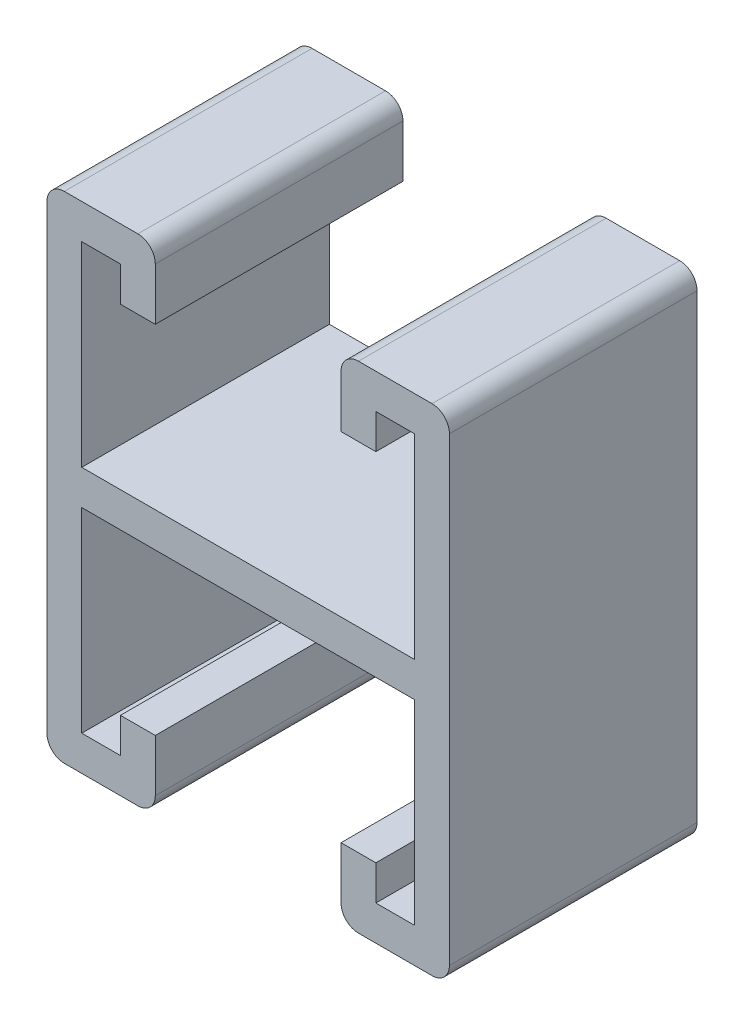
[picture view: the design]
ISO-10303-21;
HEADER;
FILE_DESCRIPTION(('STEP AP214'),'2;1');
FILE_NAME('part.step','',(''),(''),'','','');
FILE_SCHEMA(('AUTOMOTIVE_DESIGN { 1 0 10303 214 1 1 1 1 }'));
ENDSEC;
DATA;
#1=APPLICATION_CONTEXT('core data for automotive mechanical design processes');
#2=APPLICATION_PROTOCOL_DEFINITION('international standard','automotive_design',2000,#1);
#3=PRODUCT_CONTEXT('',#1,'mechanical');
#4=PRODUCT('Part','Part','',(#3));
#5=PRODUCT_RELATED_PRODUCT_CATEGORY('part','',(#4));
#6=PRODUCT_DEFINITION_FORMATION('','',#4);
#7=PRODUCT_DEFINITION_CONTEXT('part definition',#1,'design');
#8=PRODUCT_DEFINITION('design','',#6,#7);
#9=PRODUCT_DEFINITION_SHAPE('','',#8);
#10=(LENGTH_UNIT() NAMED_UNIT(*) SI_UNIT(.MILLI.,.METRE.));
#11=(NAMED_UNIT(*) PLANE_ANGLE_UNIT() SI_UNIT($,.RADIAN.));
#12=(NAMED_UNIT(*) SI_UNIT($,.STERADIAN.) SOLID_ANGLE_UNIT());
#13=UNCERTAINTY_MEASURE_WITH_UNIT(LENGTH_MEASURE(1.E-05),#10,'distance_accuracy_value','');
#14=(GEOMETRIC_REPRESENTATION_CONTEXT(3) GLOBAL_UNCERTAINTY_ASSIGNED_CONTEXT((#13)) GLOBAL_UNIT_ASSIGNED_CONTEXT((#10,
#11,#12)) REPRESENTATION_CONTEXT('',''));
#15=CARTESIAN_POINT('',(0.,0.,0.));
#16=DIRECTION('',(0.,0.,1.));
#17=DIRECTION('',(1.,0.,0.));
#18=AXIS2_PLACEMENT_3D('',#15,#16,#17);
#19=CARTESIAN_POINT('',(9.525,18.25625,12.7));
#20=DIRECTION('',(0.,1.,0.));
#21=DIRECTION('',(0.,0.,1.));
#22=AXIS2_PLACEMENT_3D('',#19,#20,#21);
#23=PLANE('',#22);
#24=DIRECTION('',(1.,0.,0.));
#25=VECTOR('',#24,1.);
#26=CARTESIAN_POINT('',(9.525,18.25625,-12.7));
#27=LINE('',#26,#25);
#28=CARTESIAN_POINT('',(9.525,18.25625,-12.7));
#29=VERTEX_POINT('',#28);
#30=CARTESIAN_POINT('',(13.096875,18.25625,-12.7));
#31=VERTEX_POINT('',#30);
#32=EDGE_CURVE('E303',#29,#31,#27,.T.);
#33=ORIENTED_EDGE('',*,*,#32,.T.);
#34=DIRECTION('',(0.,0.,-1.));
#35=VECTOR('',#34,1.);
#36=CARTESIAN_POINT('',(13.096875,18.25625,12.7));
#37=LINE('',#36,#35);
#38=CARTESIAN_POINT('',(13.096875,18.25625,12.7));
#39=VERTEX_POINT('',#38);
#40=EDGE_CURVE('E11',#39,#31,#37,.T.);
#41=ORIENTED_EDGE('',*,*,#40,.F.);
#42=DIRECTION('',(1.,0.,0.));
#43=VECTOR('',#42,1.);
#44=CARTESIAN_POINT('',(9.525,18.25625,12.7));
#45=LINE('',#44,#43);
#46=CARTESIAN_POINT('',(9.525,18.25625,12.7));
#47=VERTEX_POINT('',#46);
#48=EDGE_CURVE('E373',#47,#39,#45,.T.);
#49=ORIENTED_EDGE('',*,*,#48,.F.);
#50=DIRECTION('',(0.,0.,-1.));
#51=VECTOR('',#50,1.);
#52=CARTESIAN_POINT('',(9.525,18.25625,12.7));
#53=LINE('',#52,#51);
#54=EDGE_CURVE('E299',#47,#29,#53,.T.);
#55=ORIENTED_EDGE('',*,*,#54,.T.);
#56=EDGE_LOOP('',(#33,#41,#49,#55));
#57=FACE_BOUND('',#56,.T.);
#58=ADVANCED_FACE('F39',(#57),#23,.F.);
#59=CARTESIAN_POINT('',(13.096875,21.828125,12.7));
#60=DIRECTION('',(-1.,0.,0.));
#61=DIRECTION('',(0.,-1.,0.));
#62=AXIS2_PLACEMENT_3D('',#59,#60,#61);
#63=PLANE('',#62);
#64=DIRECTION('',(0.,1.,0.));
#65=VECTOR('',#64,1.);
#66=CARTESIAN_POINT('',(13.096875,21.828125,-12.7));
#67=LINE('',#66,#65);
#68=CARTESIAN_POINT('',(13.096875,21.828125,-12.7));
#69=VERTEX_POINT('',#68);
#70=EDGE_CURVE('E306',#31,#69,#67,.T.);
#71=ORIENTED_EDGE('',*,*,#70,.T.);
#72=DIRECTION('',(0.,0.,-1.));
#73=VECTOR('',#72,1.);
#74=CARTESIAN_POINT('',(13.096875,21.828125,12.7));
#75=LINE('',#74,#73);
#76=CARTESIAN_POINT('',(13.096875,21.828125,12.7));
#77=VERTEX_POINT('',#76);
#78=EDGE_CURVE('E50',#77,#69,#75,.T.);
#79=ORIENTED_EDGE('',*,*,#78,.F.);
#80=DIRECTION('',(0.,1.,0.));
#81=VECTOR('',#80,1.);
#82=CARTESIAN_POINT('',(13.096875,21.828125,12.7));
#83=LINE('',#82,#81);
#84=EDGE_CURVE('E185',#39,#77,#83,.T.);
#85=ORIENTED_EDGE('',*,*,#84,.F.);
#86=ORIENTED_EDGE('',*,*,#40,.T.);
#87=EDGE_LOOP('',(#71,#79,#85,#86));
#88=FACE_BOUND('',#87,.T.);
#89=ADVANCED_FACE('F571',(#88),#63,.F.);
#90=CARTESIAN_POINT('',(17.065625,21.828125,12.7));
#91=DIRECTION('',(0.,1.,0.));
#92=DIRECTION('',(0.,0.,1.));
#93=AXIS2_PLACEMENT_3D('',#90,#91,#92);
#94=PLANE('',#93);
#95=DIRECTION('',(1.,0.,0.));
#96=VECTOR('',#95,1.);
#97=CARTESIAN_POINT('',(17.065625,21.828125,-12.7));
#98=LINE('',#97,#96);
#99=CARTESIAN_POINT('',(17.065625,21.828125,-12.7));
#100=VERTEX_POINT('',#99);
#101=EDGE_CURVE('E308',#69,#100,#98,.T.);
#102=ORIENTED_EDGE('',*,*,#101,.T.);
#103=DIRECTION('',(0.,0.,-1.));
#104=VECTOR('',#103,1.);
#105=CARTESIAN_POINT('',(17.065625,21.828125,12.7));
#106=LINE('',#105,#104);
#107=CARTESIAN_POINT('',(17.065625,21.828125,12.7));
#108=VERTEX_POINT('',#107);
#109=EDGE_CURVE('E461',#108,#100,#106,.T.);
#110=ORIENTED_EDGE('',*,*,#109,.F.);
#111=DIRECTION('',(1.,0.,0.));
#112=VECTOR('',#111,1.);
#113=CARTESIAN_POINT('',(17.065625,21.828125,12.7));
#114=LINE('',#113,#112);
#115=EDGE_CURVE('E475',#77,#108,#114,.T.);
#116=ORIENTED_EDGE('',*,*,#115,.F.);
#117=ORIENTED_EDGE('',*,*,#78,.T.);
#118=EDGE_LOOP('',(#102,#110,#116,#117));
#119=FACE_BOUND('',#118,.T.);
#120=ADVANCED_FACE('F468',(#119),#94,.F.);
#121=CARTESIAN_POINT('',(17.065625,1.7859375,12.7));
#122=DIRECTION('',(1.,0.,0.));
#123=DIRECTION('',(0.,1.,0.));
#124=AXIS2_PLACEMENT_3D('',#121,#122,#123);
#125=PLANE('',#124);
#126=DIRECTION('',(0.,-1.,0.));
#127=VECTOR('',#126,1.);
#128=CARTESIAN_POINT('',(17.065625,1.7859375,-12.7));
#129=LINE('',#128,#127);
#130=CARTESIAN_POINT('',(17.065625,1.7859375,-12.7));
#131=VERTEX_POINT('',#130);
#132=EDGE_CURVE('E309',#100,#131,#129,.T.);
#133=ORIENTED_EDGE('',*,*,#132,.T.);
#134=DIRECTION('',(0.,0.,-1.));
#135=VECTOR('',#134,1.);
#136=CARTESIAN_POINT('',(17.065625,1.7859375,12.7));
#137=LINE('',#136,#135);
#138=CARTESIAN_POINT('',(17.065625,1.7859375,12.7));
#139=VERTEX_POINT('',#138);
#140=EDGE_CURVE('E462',#139,#131,#137,.T.);
#141=ORIENTED_EDGE('',*,*,#140,.F.);
#142=DIRECTION('',(0.,-1.,0.));
#143=VECTOR('',#142,1.);
#144=CARTESIAN_POINT('',(17.065625,1.7859375,12.7));
#145=LINE('',#144,#143);
#146=EDGE_CURVE('E489',#108,#139,#145,.T.);
#147=ORIENTED_EDGE('',*,*,#146,.F.);
#148=ORIENTED_EDGE('',*,*,#109,.T.);
#149=EDGE_LOOP('',(#133,#141,#147,#148));
#150=FACE_BOUND('',#149,.T.);
#151=ADVANCED_FACE('F482',(#150),#125,.F.);
#152=CARTESIAN_POINT('',(-17.065625,1.78593749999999,12.7));
#153=DIRECTION('',(0.,-1.,0.));
#154=DIRECTION('',(1.,0.,0.));
#155=AXIS2_PLACEMENT_3D('',#152,#153,#154);
#156=PLANE('',#155);
#157=DIRECTION('',(-1.,0.,0.));
#158=VECTOR('',#157,1.);
#159=CARTESIAN_POINT('',(-17.065625,1.78593749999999,-12.7));
#160=LINE('',#159,#158);
#161=CARTESIAN_POINT('',(-17.065625,1.78593749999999,-12.7));
#162=VERTEX_POINT('',#161);
#163=EDGE_CURVE('E315',#131,#162,#160,.T.);
#164=ORIENTED_EDGE('',*,*,#163,.T.);
#165=DIRECTION('',(0.,0.,-1.));
#166=VECTOR('',#165,1.);
#167=CARTESIAN_POINT('',(-17.065625,1.78593749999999,12.7));
#168=LINE('',#167,#166);
#169=CARTESIAN_POINT('',(-17.065625,1.78593749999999,12.7));
#170=VERTEX_POINT('',#169);
#171=EDGE_CURVE('E457',#170,#162,#168,.T.);
#172=ORIENTED_EDGE('',*,*,#171,.F.);
#173=DIRECTION('',(-1.,0.,0.));
#174=VECTOR('',#173,1.);
#175=CARTESIAN_POINT('',(-17.065625,1.78593749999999,12.7));
#176=LINE('',#175,#174);
#177=EDGE_CURVE('E487',#139,#170,#176,.T.);
#178=ORIENTED_EDGE('',*,*,#177,.F.);
#179=ORIENTED_EDGE('',*,*,#140,.T.);
#180=EDGE_LOOP('',(#164,#172,#178,#179));
#181=FACE_BOUND('',#180,.T.);
#182=ADVANCED_FACE('F483',(#181),#156,.F.);
#183=CARTESIAN_POINT('',(-17.065625,21.828125,12.7));
#184=DIRECTION('',(-1.,0.,0.));
#185=DIRECTION('',(0.,-1.,0.));
#186=AXIS2_PLACEMENT_3D('',#183,#184,#185);
#187=PLANE('',#186);
#188=DIRECTION('',(0.,1.,0.));
#189=VECTOR('',#188,1.);
#190=CARTESIAN_POINT('',(-17.065625,21.828125,-12.7));
#191=LINE('',#190,#189);
#192=CARTESIAN_POINT('',(-17.065625,21.828125,-12.7));
#193=VERTEX_POINT('',#192);
#194=EDGE_CURVE('E313',#162,#193,#191,.T.);
#195=ORIENTED_EDGE('',*,*,#194,.T.);
#196=DIRECTION('',(0.,0.,-1.));
#197=VECTOR('',#196,1.);
#198=CARTESIAN_POINT('',(-17.065625,21.828125,12.7));
#199=LINE('',#198,#197);
#200=CARTESIAN_POINT('',(-17.065625,21.828125,12.7));
#201=VERTEX_POINT('',#200);
#202=EDGE_CURVE('E453',#201,#193,#199,.T.);
#203=ORIENTED_EDGE('',*,*,#202,.F.);
#204=DIRECTION('',(0.,1.,0.));
#205=VECTOR('',#204,1.);
#206=CARTESIAN_POINT('',(-17.065625,21.828125,12.7));
#207=LINE('',#206,#205);
#208=EDGE_CURVE('E490',#170,#201,#207,.T.);
#209=ORIENTED_EDGE('',*,*,#208,.F.);
#210=ORIENTED_EDGE('',*,*,#171,.T.);
#211=EDGE_LOOP('',(#195,#203,#209,#210));
#212=FACE_BOUND('',#211,.T.);
#213=ADVANCED_FACE('F581',(#212),#187,.F.);
#214=CARTESIAN_POINT('',(-13.096875,21.828125,12.7));
#215=DIRECTION('',(0.,1.,0.));
#216=DIRECTION('',(0.,0.,1.));
#217=AXIS2_PLACEMENT_3D('',#214,#215,#216);
#218=PLANE('',#217);
#219=DIRECTION('',(1.,0.,0.));
#220=VECTOR('',#219,1.);
#221=CARTESIAN_POINT('',(-13.096875,21.828125,-12.7));
#222=LINE('',#221,#220);
#223=CARTESIAN_POINT('',(-13.096875,21.828125,-12.7));
#224=VERTEX_POINT('',#223);
#225=EDGE_CURVE('E317',#193,#224,#222,.T.);
#226=ORIENTED_EDGE('',*,*,#225,.T.);
#227=DIRECTION('',(0.,0.,-1.));
#228=VECTOR('',#227,1.);
#229=CARTESIAN_POINT('',(-13.096875,21.828125,12.7));
#230=LINE('',#229,#228);
#231=CARTESIAN_POINT('',(-13.096875,21.828125,12.7));
#232=VERTEX_POINT('',#231);
#233=EDGE_CURVE('E455',#232,#224,#230,.T.);
#234=ORIENTED_EDGE('',*,*,#233,.F.);
#235=DIRECTION('',(1.,0.,0.));
#236=VECTOR('',#235,1.);
#237=CARTESIAN_POINT('',(-13.096875,21.828125,12.7));
#238=LINE('',#237,#236);
#239=EDGE_CURVE('E495',#201,#232,#238,.T.);
#240=ORIENTED_EDGE('',*,*,#239,.F.);
#241=ORIENTED_EDGE('',*,*,#202,.T.);
#242=EDGE_LOOP('',(#226,#234,#240,#241));
#243=FACE_BOUND('',#242,.T.);
#244=ADVANCED_FACE('F589',(#243),#218,.F.);
#245=CARTESIAN_POINT('',(-13.096875,21.828125,12.7));
#246=DIRECTION('',(1.,0.,0.));
#247=DIRECTION('',(0.,0.,-1.));
#248=AXIS2_PLACEMENT_3D('',#245,#246,#247);
#249=PLANE('',#248);
#250=DIRECTION('',(0.,-1.,0.));
#251=VECTOR('',#250,1.);
#252=CARTESIAN_POINT('',(-13.096875,21.828125,-12.7));
#253=LINE('',#252,#251);
#254=CARTESIAN_POINT('',(-13.096875,18.25625,-12.7));
#255=VERTEX_POINT('',#254);
#256=EDGE_CURVE('E319',#224,#255,#253,.T.);
#257=ORIENTED_EDGE('',*,*,#256,.T.);
#258=DIRECTION('',(0.,0.,-1.));
#259=VECTOR('',#258,1.);
#260=CARTESIAN_POINT('',(-13.096875,18.25625,12.7));
#261=LINE('',#260,#259);
#262=CARTESIAN_POINT('',(-13.096875,18.25625,12.7));
#263=VERTEX_POINT('',#262);
#264=EDGE_CURVE('E446',#263,#255,#261,.T.);
#265=ORIENTED_EDGE('',*,*,#264,.F.);
#266=DIRECTION('',(0.,-1.,0.));
#267=VECTOR('',#266,1.);
#268=CARTESIAN_POINT('',(-13.096875,21.828125,12.7));
#269=LINE('',#268,#267);
#270=EDGE_CURVE('E498',#232,#263,#269,.T.);
#271=ORIENTED_EDGE('',*,*,#270,.F.);
#272=ORIENTED_EDGE('',*,*,#233,.T.);
#273=EDGE_LOOP('',(#257,#265,#271,#272));
#274=FACE_BOUND('',#273,.T.);
#275=ADVANCED_FACE('F592',(#274),#249,.F.);
#276=CARTESIAN_POINT('',(-13.096875,18.25625,12.7));
#277=DIRECTION('',(0.,1.,0.));
#278=DIRECTION('',(0.,0.,1.));
#279=AXIS2_PLACEMENT_3D('',#276,#277,#278);
#280=PLANE('',#279);
#281=DIRECTION('',(1.,0.,0.));
#282=VECTOR('',#281,1.);
#283=CARTESIAN_POINT('',(-13.096875,18.25625,-12.7));
#284=LINE('',#283,#282);
#285=CARTESIAN_POINT('',(-9.525,18.25625,-12.7));
#286=VERTEX_POINT('',#285);
#287=EDGE_CURVE('E318',#255,#286,#284,.T.);
#288=ORIENTED_EDGE('',*,*,#287,.T.);
#289=DIRECTION('',(0.,0.,-1.));
#290=VECTOR('',#289,1.);
#291=CARTESIAN_POINT('',(-9.525,18.25625,12.7));
#292=LINE('',#291,#290);
#293=CARTESIAN_POINT('',(-9.525,18.25625,12.7));
#294=VERTEX_POINT('',#293);
#295=EDGE_CURVE('E447',#294,#286,#292,.T.);
#296=ORIENTED_EDGE('',*,*,#295,.F.);
#297=DIRECTION('',(1.,0.,0.));
#298=VECTOR('',#297,1.);
#299=CARTESIAN_POINT('',(-13.096875,18.25625,12.7));
#300=LINE('',#299,#298);
#301=EDGE_CURVE('E499',#263,#294,#300,.T.);
#302=ORIENTED_EDGE('',*,*,#301,.F.);
#303=ORIENTED_EDGE('',*,*,#264,.T.);
#304=EDGE_LOOP('',(#288,#296,#302,#303));
#305=FACE_BOUND('',#304,.T.);
#306=ADVANCED_FACE('F593',(#305),#280,.F.);
#307=CARTESIAN_POINT('',(-9.525,23.6140625,12.7));
#308=DIRECTION('',(-1.,0.,0.));
#309=DIRECTION('',(0.,0.,1.));
#310=AXIS2_PLACEMENT_3D('',#307,#308,#309);
#311=PLANE('',#310);
#312=DIRECTION('',(0.,1.,0.));
#313=VECTOR('',#312,1.);
#314=CARTESIAN_POINT('',(-9.525,23.6140625,-12.7));
#315=LINE('',#314,#313);
#316=CARTESIAN_POINT('',(-9.525,23.6140625,-12.7));
#317=VERTEX_POINT('',#316);
#318=EDGE_CURVE('E325',#286,#317,#315,.T.);
#319=ORIENTED_EDGE('',*,*,#318,.T.);
#320=DIRECTION('',(0.,0.,-1.));
#321=VECTOR('',#320,1.);
#322=CARTESIAN_POINT('',(-9.525,23.6140625,12.7));
#323=LINE('',#322,#321);
#324=CARTESIAN_POINT('',(-9.525,23.6140625,12.7));
#325=VERTEX_POINT('',#324);
#326=EDGE_CURVE('E442',#325,#317,#323,.T.);
#327=ORIENTED_EDGE('',*,*,#326,.F.);
#328=DIRECTION('',(0.,1.,0.));
#329=VECTOR('',#328,1.);
#330=CARTESIAN_POINT('',(-9.525,23.6140625,12.7));
#331=LINE('',#330,#329);
#332=EDGE_CURVE('E505',#294,#325,#331,.T.);
#333=ORIENTED_EDGE('',*,*,#332,.F.);
#334=ORIENTED_EDGE('',*,*,#295,.T.);
#335=EDGE_LOOP('',(#319,#327,#333,#334));
#336=FACE_BOUND('',#335,.T.);
#337=ADVANCED_FACE('F599',(#336),#311,.F.);
#338=CARTESIAN_POINT('',(-11.3109375,23.6140625,12.7));
#339=DIRECTION('',(0.,0.,-1.));
#340=DIRECTION('',(-1.,0.,0.));
#341=AXIS2_PLACEMENT_3D('',#338,#339,#340);
#342=CYLINDRICAL_SURFACE('',#341,1.7859375);
#343=CARTESIAN_POINT('',(-11.3109375,23.6140625,-12.7));
#344=DIRECTION('',(0.,0.,1.));
#345=DIRECTION('',(-1.,0.,0.));
#346=AXIS2_PLACEMENT_3D('',#343,#344,#345);
#347=CIRCLE('',#346,1.7859375);
#348=CARTESIAN_POINT('',(-11.3109375,25.4,-12.7));
#349=VERTEX_POINT('',#348);
#350=EDGE_CURVE('E321',#317,#349,#347,.T.);
#351=ORIENTED_EDGE('',*,*,#350,.T.);
#352=DIRECTION('',(0.,0.,-1.));
#353=VECTOR('',#352,1.);
#354=CARTESIAN_POINT('',(-11.3109375,25.4,12.7));
#355=LINE('',#354,#353);
#356=CARTESIAN_POINT('',(-11.3109375,25.4,12.7));
#357=VERTEX_POINT('',#356);
#358=EDGE_CURVE('E439',#357,#349,#355,.T.);
#359=ORIENTED_EDGE('',*,*,#358,.F.);
#360=CARTESIAN_POINT('',(-11.3109375,23.6140625,12.7));
#361=DIRECTION('',(0.,0.,1.));
#362=DIRECTION('',(-1.,0.,0.));
#363=AXIS2_PLACEMENT_3D('',#360,#361,#362);
#364=CIRCLE('',#363,1.7859375);
#365=EDGE_CURVE('E502',#325,#357,#364,.T.);
#366=ORIENTED_EDGE('',*,*,#365,.F.);
#367=ORIENTED_EDGE('',*,*,#326,.T.);
#368=EDGE_LOOP('',(#351,#359,#366,#367));
#369=FACE_BOUND('',#368,.T.);
#370=ADVANCED_FACE('F604',(#369),#342,.T.);
#371=CARTESIAN_POINT('',(-11.3109375,25.4,12.7));
#372=DIRECTION('',(0.,-1.,0.));
#373=DIRECTION('',(1.,0.,0.));
#374=AXIS2_PLACEMENT_3D('',#371,#372,#373);
#375=PLANE('',#374);
#376=DIRECTION('',(-1.,0.,0.));
#377=VECTOR('',#376,1.);
#378=CARTESIAN_POINT('',(-11.3109375,25.4,-12.7));
#379=LINE('',#378,#377);
#380=CARTESIAN_POINT('',(-18.8515625,25.4,-12.7));
#381=VERTEX_POINT('',#380);
#382=EDGE_CURVE('E328',#349,#381,#379,.T.);
#383=ORIENTED_EDGE('',*,*,#382,.T.);
#384=DIRECTION('',(0.,0.,-1.));
#385=VECTOR('',#384,1.);
#386=CARTESIAN_POINT('',(-18.8515625,25.4,12.7));
#387=LINE('',#386,#385);
#388=CARTESIAN_POINT('',(-18.8515625,25.4,12.7));
#389=VERTEX_POINT('',#388);
#390=EDGE_CURVE('E440',#389,#381,#387,.T.);
#391=ORIENTED_EDGE('',*,*,#390,.F.);
#392=DIRECTION('',(-1.,0.,0.));
#393=VECTOR('',#392,1.);
#394=CARTESIAN_POINT('',(-11.3109375,25.4,12.7));
#395=LINE('',#394,#393);
#396=EDGE_CURVE('E506',#357,#389,#395,.T.);
#397=ORIENTED_EDGE('',*,*,#396,.F.);
#398=ORIENTED_EDGE('',*,*,#358,.T.);
#399=EDGE_LOOP('',(#383,#391,#397,#398));
#400=FACE_BOUND('',#399,.T.);
#401=ADVANCED_FACE('F609',(#400),#375,.F.);
#402=CARTESIAN_POINT('',(-18.8515625,23.6140625,12.7));
#403=DIRECTION('',(0.,0.,-1.));
#404=DIRECTION('',(-1.,0.,0.));
#405=AXIS2_PLACEMENT_3D('',#402,#403,#404);
#406=CYLINDRICAL_SURFACE('',#405,1.7859375);
#407=CARTESIAN_POINT('',(-18.8515625,23.6140625,-12.7));
#408=DIRECTION('',(0.,0.,1.));
#409=DIRECTION('',(-1.,0.,0.));
#410=AXIS2_PLACEMENT_3D('',#407,#408,#409);
#411=CIRCLE('',#410,1.7859375);
#412=CARTESIAN_POINT('',(-20.6375,23.6140625,-12.7));
#413=VERTEX_POINT('',#412);
#414=EDGE_CURVE('E327',#381,#413,#411,.T.);
#415=ORIENTED_EDGE('',*,*,#414,.T.);
#416=DIRECTION('',(0.,0.,-1.));
#417=VECTOR('',#416,1.);
#418=CARTESIAN_POINT('',(-20.6375,23.6140625,12.7));
#419=LINE('',#418,#417);
#420=CARTESIAN_POINT('',(-20.6375,23.6140625,12.7));
#421=VERTEX_POINT('',#420);
#422=EDGE_CURVE('E432',#421,#413,#419,.T.);
#423=ORIENTED_EDGE('',*,*,#422,.F.);
#424=CARTESIAN_POINT('',(-18.8515625,23.6140625,12.7));
#425=DIRECTION('',(0.,0.,1.));
#426=DIRECTION('',(-1.,0.,0.));
#427=AXIS2_PLACEMENT_3D('',#424,#425,#426);
#428=CIRCLE('',#427,1.7859375);
#429=EDGE_CURVE('E507',#389,#421,#428,.T.);
#430=ORIENTED_EDGE('',*,*,#429,.F.);
#431=ORIENTED_EDGE('',*,*,#390,.T.);
#432=EDGE_LOOP('',(#415,#423,#430,#431));
#433=FACE_BOUND('',#432,.T.);
#434=ADVANCED_FACE('F612',(#433),#406,.T.);
#435=CARTESIAN_POINT('',(-20.6375,23.6140625,12.7));
#436=DIRECTION('',(1.,0.,0.));
#437=DIRECTION('',(0.,1.,0.));
#438=AXIS2_PLACEMENT_3D('',#435,#436,#437);
#439=PLANE('',#438);
#440=DIRECTION('',(0.,-1.,0.));
#441=VECTOR('',#440,1.);
#442=CARTESIAN_POINT('',(-20.6375,23.6140625,-12.7));
#443=LINE('',#442,#441);
#444=CARTESIAN_POINT('',(-20.6375,-23.6140625,-12.7));
#445=VERTEX_POINT('',#444);
#446=EDGE_CURVE('E326',#413,#445,#443,.T.);
#447=ORIENTED_EDGE('',*,*,#446,.T.);
#448=DIRECTION('',(0.,0.,-1.));
#449=VECTOR('',#448,1.);
#450=CARTESIAN_POINT('',(-20.6375,-23.6140625,12.7));
#451=LINE('',#450,#449);
#452=CARTESIAN_POINT('',(-20.6375,-23.6140625,12.7));
#453=VERTEX_POINT('',#452);
#454=EDGE_CURVE('E431',#453,#445,#451,.T.);
#455=ORIENTED_EDGE('',*,*,#454,.F.);
#456=DIRECTION('',(0.,-1.,0.));
#457=VECTOR('',#456,1.);
#458=CARTESIAN_POINT('',(-20.6375,23.6140625,12.7));
#459=LINE('',#458,#457);
#460=EDGE_CURVE('E509',#421,#453,#459,.T.);
#461=ORIENTED_EDGE('',*,*,#460,.F.);
#462=ORIENTED_EDGE('',*,*,#422,.T.);
#463=EDGE_LOOP('',(#447,#455,#461,#462));
#464=FACE_BOUND('',#463,.T.);
#465=ADVANCED_FACE('F613',(#464),#439,.F.);
#466=CARTESIAN_POINT('',(-18.8515625,-23.6140625,12.7));
#467=DIRECTION('',(0.,0.,-1.));
#468=DIRECTION('',(-1.,0.,0.));
#469=AXIS2_PLACEMENT_3D('',#466,#467,#468);
#470=CYLINDRICAL_SURFACE('',#469,1.7859375);
#471=CARTESIAN_POINT('',(-18.8515625,-23.6140625,-12.7));
#472=DIRECTION('',(0.,0.,1.));
#473=DIRECTION('',(1.,0.,0.));
#474=AXIS2_PLACEMENT_3D('',#471,#472,#473);
#475=CIRCLE('',#474,1.7859375);
#476=CARTESIAN_POINT('',(-18.8515625,-25.4,-12.7));
#477=VERTEX_POINT('',#476);
#478=EDGE_CURVE('E334',#445,#477,#475,.T.);
#479=ORIENTED_EDGE('',*,*,#478,.T.);
#480=DIRECTION('',(0.,0.,-1.));
#481=VECTOR('',#480,1.);
#482=CARTESIAN_POINT('',(-18.8515625,-25.4,12.7));
#483=LINE('',#482,#481);
#484=CARTESIAN_POINT('',(-18.8515625,-25.4,12.7));
#485=VERTEX_POINT('',#484);
#486=EDGE_CURVE('E426',#485,#477,#483,.T.);
#487=ORIENTED_EDGE('',*,*,#486,.F.);
#488=CARTESIAN_POINT('',(-18.8515625,-23.6140625,12.7));
#489=DIRECTION('',(0.,0.,1.));
#490=DIRECTION('',(1.,0.,0.));
#491=AXIS2_PLACEMENT_3D('',#488,#489,#490);
#492=CIRCLE('',#491,1.7859375);
#493=EDGE_CURVE('E515',#453,#485,#492,.T.);
#494=ORIENTED_EDGE('',*,*,#493,.F.);
#495=ORIENTED_EDGE('',*,*,#454,.T.);
#496=EDGE_LOOP('',(#479,#487,#494,#495));
#497=FACE_BOUND('',#496,.T.);
#498=ADVANCED_FACE('F620',(#497),#470,.T.);
#499=CARTESIAN_POINT('',(-11.3109375,-25.4,12.7));
#500=DIRECTION('',(0.,1.,0.));
#501=DIRECTION('',(-1.,0.,0.));
#502=AXIS2_PLACEMENT_3D('',#499,#500,#501);
#503=PLANE('',#502);
#504=DIRECTION('',(1.,0.,0.));
#505=VECTOR('',#504,1.);
#506=CARTESIAN_POINT('',(-11.3109375,-25.4,-12.7));
#507=LINE('',#506,#505);
#508=CARTESIAN_POINT('',(-11.3109375,-25.4,-12.7));
#509=VERTEX_POINT('',#508);
#510=EDGE_CURVE('E331',#477,#509,#507,.T.);
#511=ORIENTED_EDGE('',*,*,#510,.T.);
#512=DIRECTION('',(0.,0.,-1.));
#513=VECTOR('',#512,1.);
#514=CARTESIAN_POINT('',(-11.3109375,-25.4,12.7));
#515=LINE('',#514,#513);
#516=CARTESIAN_POINT('',(-11.3109375,-25.4,12.7));
#517=VERTEX_POINT('',#516);
#518=EDGE_CURVE('E424',#517,#509,#515,.T.);
#519=ORIENTED_EDGE('',*,*,#518,.F.);
#520=DIRECTION('',(1.,0.,0.));
#521=VECTOR('',#520,1.);
#522=CARTESIAN_POINT('',(-11.3109375,-25.4,12.7));
#523=LINE('',#522,#521);
#524=EDGE_CURVE('E511',#485,#517,#523,.T.);
#525=ORIENTED_EDGE('',*,*,#524,.F.);
#526=ORIENTED_EDGE('',*,*,#486,.T.);
#527=EDGE_LOOP('',(#511,#519,#525,#526));
#528=FACE_BOUND('',#527,.T.);
#529=ADVANCED_FACE('F621',(#528),#503,.F.);
#530=CARTESIAN_POINT('',(-11.3109375,-23.6140625,12.7));
#531=DIRECTION('',(0.,0.,-1.));
#532=DIRECTION('',(-1.,0.,0.));
#533=AXIS2_PLACEMENT_3D('',#530,#531,#532);
#534=CYLINDRICAL_SURFACE('',#533,1.7859375);
#535=CARTESIAN_POINT('',(-11.3109375,-23.6140625,-12.7));
#536=DIRECTION('',(0.,0.,1.));
#537=DIRECTION('',(1.,0.,0.));
#538=AXIS2_PLACEMENT_3D('',#535,#536,#537);
#539=CIRCLE('',#538,1.7859375);
#540=CARTESIAN_POINT('',(-9.525,-23.6140625,-12.7));
#541=VERTEX_POINT('',#540);
#542=EDGE_CURVE('E337',#509,#541,#539,.T.);
#543=ORIENTED_EDGE('',*,*,#542,.T.);
#544=DIRECTION('',(0.,0.,-1.));
#545=VECTOR('',#544,1.);
#546=CARTESIAN_POINT('',(-9.525,-23.6140625,12.7));
#547=LINE('',#546,#545);
#548=CARTESIAN_POINT('',(-9.525,-23.6140625,12.7));
#549=VERTEX_POINT('',#548);
#550=EDGE_CURVE('E422',#549,#541,#547,.T.);
#551=ORIENTED_EDGE('',*,*,#550,.F.);
#552=CARTESIAN_POINT('',(-11.3109375,-23.6140625,12.7));
#553=DIRECTION('',(0.,0.,1.));
#554=DIRECTION('',(1.,0.,0.));
#555=AXIS2_PLACEMENT_3D('',#552,#553,#554);
#556=CIRCLE('',#555,1.7859375);
#557=EDGE_CURVE('E517',#517,#549,#556,.T.);
#558=ORIENTED_EDGE('',*,*,#557,.F.);
#559=ORIENTED_EDGE('',*,*,#518,.T.);
#560=EDGE_LOOP('',(#543,#551,#558,#559));
#561=FACE_BOUND('',#560,.T.);
#562=ADVANCED_FACE('F630',(#561),#534,.T.);
#563=CARTESIAN_POINT('',(-9.525,-23.6140625,12.7));
#564=DIRECTION('',(-1.,0.,0.));
#565=DIRECTION('',(0.,0.,1.));
#566=AXIS2_PLACEMENT_3D('',#563,#564,#565);
#567=PLANE('',#566);
#568=DIRECTION('',(0.,1.,0.));
#569=VECTOR('',#568,1.);
#570=CARTESIAN_POINT('',(-9.525,-23.6140625,-12.7));
#571=LINE('',#570,#569);
#572=CARTESIAN_POINT('',(-9.525,-18.25625,-12.7));
#573=VERTEX_POINT('',#572);
#574=EDGE_CURVE('E336',#541,#573,#571,.T.);
#575=ORIENTED_EDGE('',*,*,#574,.T.);
#576=DIRECTION('',(0.,0.,-1.));
#577=VECTOR('',#576,1.);
#578=CARTESIAN_POINT('',(-9.525,-18.25625,12.7));
#579=LINE('',#578,#577);
#580=CARTESIAN_POINT('',(-9.525,-18.25625,12.7));
#581=VERTEX_POINT('',#580);
#582=EDGE_CURVE('E416',#581,#573,#579,.T.);
#583=ORIENTED_EDGE('',*,*,#582,.F.);
#584=DIRECTION('',(0.,1.,0.));
#585=VECTOR('',#584,1.);
#586=CARTESIAN_POINT('',(-9.525,-23.6140625,12.7));
#587=LINE('',#586,#585);
#588=EDGE_CURVE('E519',#549,#581,#587,.T.);
#589=ORIENTED_EDGE('',*,*,#588,.F.);
#590=ORIENTED_EDGE('',*,*,#550,.T.);
#591=EDGE_LOOP('',(#575,#583,#589,#590));
#592=FACE_BOUND('',#591,.T.);
#593=ADVANCED_FACE('F631',(#592),#567,.F.);
#594=CARTESIAN_POINT('',(-13.096875,-18.25625,12.7));
#595=DIRECTION('',(0.,-1.,0.));
#596=DIRECTION('',(0.,0.,-1.));
#597=AXIS2_PLACEMENT_3D('',#594,#595,#596);
#598=PLANE('',#597);
#599=DIRECTION('',(-1.,0.,0.));
#600=VECTOR('',#599,1.);
#601=CARTESIAN_POINT('',(-13.096875,-18.25625,-12.7));
#602=LINE('',#601,#600);
#603=CARTESIAN_POINT('',(-13.096875,-18.25625,-12.7));
#604=VERTEX_POINT('',#603);
#605=EDGE_CURVE('E338',#573,#604,#602,.T.);
#606=ORIENTED_EDGE('',*,*,#605,.T.);
#607=DIRECTION('',(0.,0.,-1.));
#608=VECTOR('',#607,1.);
#609=CARTESIAN_POINT('',(-13.096875,-18.25625,12.7));
#610=LINE('',#609,#608);
#611=CARTESIAN_POINT('',(-13.096875,-18.25625,12.7));
#612=VERTEX_POINT('',#611);
#613=EDGE_CURVE('E417',#612,#604,#610,.T.);
#614=ORIENTED_EDGE('',*,*,#613,.F.);
#615=DIRECTION('',(-1.,0.,0.));
#616=VECTOR('',#615,1.);
#617=CARTESIAN_POINT('',(-13.096875,-18.25625,12.7));
#618=LINE('',#617,#616);
#619=EDGE_CURVE('E518',#581,#612,#618,.T.);
#620=ORIENTED_EDGE('',*,*,#619,.F.);
#621=ORIENTED_EDGE('',*,*,#582,.T.);
#622=EDGE_LOOP('',(#606,#614,#620,#621));
#623=FACE_BOUND('',#622,.T.);
#624=ADVANCED_FACE('F634',(#623),#598,.F.);
#625=CARTESIAN_POINT('',(-13.096875,-21.828125,12.7));
#626=DIRECTION('',(1.,0.,0.));
#627=DIRECTION('',(0.,0.,-1.));
#628=AXIS2_PLACEMENT_3D('',#625,#626,#627);
#629=PLANE('',#628);
#630=DIRECTION('',(0.,-1.,0.));
#631=VECTOR('',#630,1.);
#632=CARTESIAN_POINT('',(-13.096875,-21.828125,-12.7));
#633=LINE('',#632,#631);
#634=CARTESIAN_POINT('',(-13.096875,-21.828125,-12.7));
#635=VERTEX_POINT('',#634);
#636=EDGE_CURVE('E345',#604,#635,#633,.T.);
#637=ORIENTED_EDGE('',*,*,#636,.T.);
#638=DIRECTION('',(0.,0.,-1.));
#639=VECTOR('',#638,1.);
#640=CARTESIAN_POINT('',(-13.096875,-21.828125,12.7));
#641=LINE('',#640,#639);
#642=CARTESIAN_POINT('',(-13.096875,-21.828125,12.7));
#643=VERTEX_POINT('',#642);
#644=EDGE_CURVE('E412',#643,#635,#641,.T.);
#645=ORIENTED_EDGE('',*,*,#644,.F.);
#646=DIRECTION('',(0.,-1.,0.));
#647=VECTOR('',#646,1.);
#648=CARTESIAN_POINT('',(-13.096875,-21.828125,12.7));
#649=LINE('',#648,#647);
#650=EDGE_CURVE('E524',#612,#643,#649,.T.);
#651=ORIENTED_EDGE('',*,*,#650,.F.);
#652=ORIENTED_EDGE('',*,*,#613,.T.);
#653=EDGE_LOOP('',(#637,#645,#651,#652));
#654=FACE_BOUND('',#653,.T.);
#655=ADVANCED_FACE('F638',(#654),#629,.F.);
#656=CARTESIAN_POINT('',(-13.096875,-21.828125,12.7));
#657=DIRECTION('',(0.,-1.,0.));
#658=DIRECTION('',(1.,0.,0.));
#659=AXIS2_PLACEMENT_3D('',#656,#657,#658);
#660=PLANE('',#659);
#661=DIRECTION('',(-1.,0.,0.));
#662=VECTOR('',#661,1.);
#663=CARTESIAN_POINT('',(-13.096875,-21.828125,-12.7));
#664=LINE('',#663,#662);
#665=CARTESIAN_POINT('',(-17.065625,-21.828125,-12.7));
#666=VERTEX_POINT('',#665);
#667=EDGE_CURVE('E341',#635,#666,#664,.T.);
#668=ORIENTED_EDGE('',*,*,#667,.T.);
#669=DIRECTION('',(0.,0.,-1.));
#670=VECTOR('',#669,1.);
#671=CARTESIAN_POINT('',(-17.065625,-21.828125,12.7));
#672=LINE('',#671,#670);
#673=CARTESIAN_POINT('',(-17.065625,-21.828125,12.7));
#674=VERTEX_POINT('',#673);
#675=EDGE_CURVE('E408',#674,#666,#672,.T.);
#676=ORIENTED_EDGE('',*,*,#675,.F.);
#677=DIRECTION('',(-1.,0.,0.));
#678=VECTOR('',#677,1.);
#679=CARTESIAN_POINT('',(-13.096875,-21.828125,12.7));
#680=LINE('',#679,#678);
#681=EDGE_CURVE('E525',#643,#674,#680,.T.);
#682=ORIENTED_EDGE('',*,*,#681,.F.);
#683=ORIENTED_EDGE('',*,*,#644,.T.);
#684=EDGE_LOOP('',(#668,#676,#682,#683));
#685=FACE_BOUND('',#684,.T.);
#686=ADVANCED_FACE('F644',(#685),#660,.F.);
#687=CARTESIAN_POINT('',(-17.065625,-21.828125,12.7));
#688=DIRECTION('',(-1.,0.,0.));
#689=DIRECTION('',(0.,-1.,0.));
#690=AXIS2_PLACEMENT_3D('',#687,#688,#689);
#691=PLANE('',#690);
#692=DIRECTION('',(0.,1.,0.));
#693=VECTOR('',#692,1.);
#694=CARTESIAN_POINT('',(-17.065625,-21.828125,-12.7));
#695=LINE('',#694,#693);
#696=CARTESIAN_POINT('',(-17.065625,-1.7859375,-12.7));
#697=VERTEX_POINT('',#696);
#698=EDGE_CURVE('E348',#666,#697,#695,.T.);
#699=ORIENTED_EDGE('',*,*,#698,.T.);
#700=DIRECTION('',(0.,0.,-1.));
#701=VECTOR('',#700,1.);
#702=CARTESIAN_POINT('',(-17.065625,-1.7859375,12.7));
#703=LINE('',#702,#701);
#704=CARTESIAN_POINT('',(-17.065625,-1.7859375,12.7));
#705=VERTEX_POINT('',#704);
#706=EDGE_CURVE('E410',#705,#697,#703,.T.);
#707=ORIENTED_EDGE('',*,*,#706,.F.);
#708=DIRECTION('',(0.,1.,0.));
#709=VECTOR('',#708,1.);
#710=CARTESIAN_POINT('',(-17.065625,-21.828125,12.7));
#711=LINE('',#710,#709);
#712=EDGE_CURVE('E527',#674,#705,#711,.T.);
#713=ORIENTED_EDGE('',*,*,#712,.F.);
#714=ORIENTED_EDGE('',*,*,#675,.T.);
#715=EDGE_LOOP('',(#699,#707,#713,#714));
#716=FACE_BOUND('',#715,.T.);
#717=ADVANCED_FACE('F650',(#716),#691,.F.);
#718=CARTESIAN_POINT('',(-17.065625,-1.7859375,12.7));
#719=DIRECTION('',(0.,1.,0.));
#720=DIRECTION('',(0.,0.,1.));
#721=AXIS2_PLACEMENT_3D('',#718,#719,#720);
#722=PLANE('',#721);
#723=DIRECTION('',(1.,0.,0.));
#724=VECTOR('',#723,1.);
#725=CARTESIAN_POINT('',(-17.065625,-1.7859375,-12.7));
#726=LINE('',#725,#724);
#727=CARTESIAN_POINT('',(17.065625,-1.7859375,-12.7));
#728=VERTEX_POINT('',#727);
#729=EDGE_CURVE('E347',#697,#728,#726,.T.);
#730=ORIENTED_EDGE('',*,*,#729,.T.);
#731=DIRECTION('',(0.,0.,-1.));
#732=VECTOR('',#731,1.);
#733=CARTESIAN_POINT('',(17.065625,-1.7859375,12.7));
#734=LINE('',#733,#732);
#735=CARTESIAN_POINT('',(17.065625,-1.7859375,12.7));
#736=VERTEX_POINT('',#735);
#737=EDGE_CURVE('E404',#736,#728,#734,.T.);
#738=ORIENTED_EDGE('',*,*,#737,.F.);
#739=DIRECTION('',(1.,0.,0.));
#740=VECTOR('',#739,1.);
#741=CARTESIAN_POINT('',(-17.065625,-1.7859375,12.7));
#742=LINE('',#741,#740);
#743=EDGE_CURVE('E530',#705,#736,#742,.T.);
#744=ORIENTED_EDGE('',*,*,#743,.F.);
#745=ORIENTED_EDGE('',*,*,#706,.T.);
#746=EDGE_LOOP('',(#730,#738,#744,#745));
#747=FACE_BOUND('',#746,.T.);
#748=ADVANCED_FACE('F653',(#747),#722,.F.);
#749=CARTESIAN_POINT('',(17.065625,-1.7859375,12.7));
#750=DIRECTION('',(1.,0.,0.));
#751=DIRECTION('',(0.,1.,0.));
#752=AXIS2_PLACEMENT_3D('',#749,#750,#751);
#753=PLANE('',#752);
#754=DIRECTION('',(0.,-1.,0.));
#755=VECTOR('',#754,1.);
#756=CARTESIAN_POINT('',(17.065625,-1.7859375,-12.7));
#757=LINE('',#756,#755);
#758=CARTESIAN_POINT('',(17.065625,-21.828125,-12.7));
#759=VERTEX_POINT('',#758);
#760=EDGE_CURVE('E346',#728,#759,#757,.T.);
#761=ORIENTED_EDGE('',*,*,#760,.T.);
#762=DIRECTION('',(0.,0.,-1.));
#763=VECTOR('',#762,1.);
#764=CARTESIAN_POINT('',(17.065625,-21.828125,12.7));
#765=LINE('',#764,#763);
#766=CARTESIAN_POINT('',(17.065625,-21.828125,12.7));
#767=VERTEX_POINT('',#766);
#768=EDGE_CURVE('E402',#767,#759,#765,.T.);
#769=ORIENTED_EDGE('',*,*,#768,.F.);
#770=DIRECTION('',(0.,-1.,0.));
#771=VECTOR('',#770,1.);
#772=CARTESIAN_POINT('',(17.065625,-1.7859375,12.7));
#773=LINE('',#772,#771);
#774=EDGE_CURVE('E528',#736,#767,#773,.T.);
#775=ORIENTED_EDGE('',*,*,#774,.F.);
#776=ORIENTED_EDGE('',*,*,#737,.T.);
#777=EDGE_LOOP('',(#761,#769,#775,#776));
#778=FACE_BOUND('',#777,.T.);
#779=ADVANCED_FACE('F651',(#778),#753,.F.);
#780=CARTESIAN_POINT('',(17.065625,-21.828125,12.7));
#781=DIRECTION('',(0.,-1.,0.));
#782=DIRECTION('',(0.,0.,-1.));
#783=AXIS2_PLACEMENT_3D('',#780,#781,#782);
#784=PLANE('',#783);
#785=DIRECTION('',(-1.,0.,0.));
#786=VECTOR('',#785,1.);
#787=CARTESIAN_POINT('',(17.065625,-21.828125,-12.7));
#788=LINE('',#787,#786);
#789=CARTESIAN_POINT('',(13.096875,-21.828125,-12.7));
#790=VERTEX_POINT('',#789);
#791=EDGE_CURVE('E354',#759,#790,#788,.T.);
#792=ORIENTED_EDGE('',*,*,#791,.T.);
#793=DIRECTION('',(0.,0.,-1.));
#794=VECTOR('',#793,1.);
#795=CARTESIAN_POINT('',(13.096875,-21.828125,12.7));
#796=LINE('',#795,#794);
#797=CARTESIAN_POINT('',(13.096875,-21.828125,12.7));
#798=VERTEX_POINT('',#797);
#799=EDGE_CURVE('E400',#798,#790,#796,.T.);
#800=ORIENTED_EDGE('',*,*,#799,.F.);
#801=DIRECTION('',(-1.,0.,0.));
#802=VECTOR('',#801,1.);
#803=CARTESIAN_POINT('',(17.065625,-21.828125,12.7));
#804=LINE('',#803,#802);
#805=EDGE_CURVE('E535',#767,#798,#804,.T.);
#806=ORIENTED_EDGE('',*,*,#805,.F.);
#807=ORIENTED_EDGE('',*,*,#768,.T.);
#808=EDGE_LOOP('',(#792,#800,#806,#807));
#809=FACE_BOUND('',#808,.T.);
#810=ADVANCED_FACE('F656',(#809),#784,.F.);
#811=CARTESIAN_POINT('',(13.096875,-21.828125,12.7));
#812=DIRECTION('',(-1.,0.,0.));
#813=DIRECTION('',(0.,-1.,0.));
#814=AXIS2_PLACEMENT_3D('',#811,#812,#813);
#815=PLANE('',#814);
#816=DIRECTION('',(0.,1.,0.));
#817=VECTOR('',#816,1.);
#818=CARTESIAN_POINT('',(13.096875,-21.828125,-12.7));
#819=LINE('',#818,#817);
#820=CARTESIAN_POINT('',(13.096875,-18.25625,-12.7));
#821=VERTEX_POINT('',#820);
#822=EDGE_CURVE('E351',#790,#821,#819,.T.);
#823=ORIENTED_EDGE('',*,*,#822,.T.);
#824=DIRECTION('',(0.,0.,-1.));
#825=VECTOR('',#824,1.);
#826=CARTESIAN_POINT('',(13.096875,-18.25625,12.7));
#827=LINE('',#826,#825);
#828=CARTESIAN_POINT('',(13.096875,-18.25625,12.7));
#829=VERTEX_POINT('',#828);
#830=EDGE_CURVE('E391',#829,#821,#827,.T.);
#831=ORIENTED_EDGE('',*,*,#830,.F.);
#832=DIRECTION('',(0.,1.,0.));
#833=VECTOR('',#832,1.);
#834=CARTESIAN_POINT('',(13.096875,-21.828125,12.7));
#835=LINE('',#834,#833);
#836=EDGE_CURVE('E534',#798,#829,#835,.T.);
#837=ORIENTED_EDGE('',*,*,#836,.F.);
#838=ORIENTED_EDGE('',*,*,#799,.T.);
#839=EDGE_LOOP('',(#823,#831,#837,#838));
#840=FACE_BOUND('',#839,.T.);
#841=ADVANCED_FACE('F661',(#840),#815,.F.);
#842=CARTESIAN_POINT('',(9.525,-18.25625,12.7));
#843=DIRECTION('',(0.,-1.,0.));
#844=DIRECTION('',(1.,0.,0.));
#845=AXIS2_PLACEMENT_3D('',#842,#843,#844);
#846=PLANE('',#845);
#847=DIRECTION('',(-1.,0.,0.));
#848=VECTOR('',#847,1.);
#849=CARTESIAN_POINT('',(9.525,-18.25625,-12.7));
#850=LINE('',#849,#848);
#851=CARTESIAN_POINT('',(9.525,-18.25625,-12.7));
#852=VERTEX_POINT('',#851);
#853=EDGE_CURVE('E358',#821,#852,#850,.T.);
#854=ORIENTED_EDGE('',*,*,#853,.T.);
#855=DIRECTION('',(0.,0.,-1.));
#856=VECTOR('',#855,1.);
#857=CARTESIAN_POINT('',(9.525,-18.25625,12.7));
#858=LINE('',#857,#856);
#859=CARTESIAN_POINT('',(9.525,-18.25625,12.7));
#860=VERTEX_POINT('',#859);
#861=EDGE_CURVE('E394',#860,#852,#858,.T.);
#862=ORIENTED_EDGE('',*,*,#861,.F.);
#863=DIRECTION('',(-1.,0.,0.));
#864=VECTOR('',#863,1.);
#865=CARTESIAN_POINT('',(9.525,-18.25625,12.7));
#866=LINE('',#865,#864);
#867=EDGE_CURVE('E537',#829,#860,#866,.T.);
#868=ORIENTED_EDGE('',*,*,#867,.F.);
#869=ORIENTED_EDGE('',*,*,#830,.T.);
#870=EDGE_LOOP('',(#854,#862,#868,#869));
#871=FACE_BOUND('',#870,.T.);
#872=ADVANCED_FACE('F670',(#871),#846,.F.);
#873=CARTESIAN_POINT('',(9.525,-23.6140625,12.7));
#874=DIRECTION('',(1.,0.,0.));
#875=DIRECTION('',(0.,1.,0.));
#876=AXIS2_PLACEMENT_3D('',#873,#874,#875);
#877=PLANE('',#876);
#878=DIRECTION('',(0.,-1.,0.));
#879=VECTOR('',#878,1.);
#880=CARTESIAN_POINT('',(9.525,-23.6140625,-12.7));
#881=LINE('',#880,#879);
#882=CARTESIAN_POINT('',(9.52500000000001,-23.6140625,-12.7));
#883=VERTEX_POINT('',#882);
#884=EDGE_CURVE('E356',#852,#883,#881,.T.);
#885=ORIENTED_EDGE('',*,*,#884,.T.);
#886=DIRECTION('',(0.,0.,-1.));
#887=VECTOR('',#886,1.);
#888=CARTESIAN_POINT('',(9.52500000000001,-23.6140625,12.7));
#889=LINE('',#888,#887);
#890=CARTESIAN_POINT('',(9.52500000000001,-23.6140625,12.7));
#891=VERTEX_POINT('',#890);
#892=EDGE_CURVE('E386',#891,#883,#889,.T.);
#893=ORIENTED_EDGE('',*,*,#892,.F.);
#894=DIRECTION('',(0.,-1.,0.));
#895=VECTOR('',#894,1.);
#896=CARTESIAN_POINT('',(9.525,-23.6140625,12.7));
#897=LINE('',#896,#895);
#898=EDGE_CURVE('E539',#860,#891,#897,.T.);
#899=ORIENTED_EDGE('',*,*,#898,.F.);
#900=ORIENTED_EDGE('',*,*,#861,.T.);
#901=EDGE_LOOP('',(#885,#893,#899,#900));
#902=FACE_BOUND('',#901,.T.);
#903=ADVANCED_FACE('F673',(#902),#877,.F.);
#904=CARTESIAN_POINT('',(11.3109375,-23.6140625,12.7));
#905=DIRECTION('',(0.,0.,-1.));
#906=DIRECTION('',(-1.,0.,0.));
#907=AXIS2_PLACEMENT_3D('',#904,#905,#906);
#908=CYLINDRICAL_SURFACE('',#907,1.7859375);
#909=CARTESIAN_POINT('',(11.3109375,-23.6140625,-12.7));
#910=DIRECTION('',(0.,0.,1.));
#911=DIRECTION('',(1.,0.,0.));
#912=AXIS2_PLACEMENT_3D('',#909,#910,#911);
#913=CIRCLE('',#912,1.7859375);
#914=CARTESIAN_POINT('',(11.3109375,-25.4,-12.7));
#915=VERTEX_POINT('',#914);
#916=EDGE_CURVE('E359',#883,#915,#913,.T.);
#917=ORIENTED_EDGE('',*,*,#916,.T.);
#918=DIRECTION('',(0.,0.,-1.));
#919=VECTOR('',#918,1.);
#920=CARTESIAN_POINT('',(11.3109375,-25.4,12.7));
#921=LINE('',#920,#919);
#922=CARTESIAN_POINT('',(11.3109375,-25.4,12.7));
#923=VERTEX_POINT('',#922);
#924=EDGE_CURVE('E387',#923,#915,#921,.T.);
#925=ORIENTED_EDGE('',*,*,#924,.F.);
#926=CARTESIAN_POINT('',(11.3109375,-23.6140625,12.7));
#927=DIRECTION('',(0.,0.,1.));
#928=DIRECTION('',(1.,0.,0.));
#929=AXIS2_PLACEMENT_3D('',#926,#927,#928);
#930=CIRCLE('',#929,1.7859375);
#931=EDGE_CURVE('E538',#891,#923,#930,.T.);
#932=ORIENTED_EDGE('',*,*,#931,.F.);
#933=ORIENTED_EDGE('',*,*,#892,.T.);
#934=EDGE_LOOP('',(#917,#925,#932,#933));
#935=FACE_BOUND('',#934,.T.);
#936=ADVANCED_FACE('F671',(#935),#908,.T.);
#937=CARTESIAN_POINT('',(18.8515625,-25.4,12.7));
#938=DIRECTION('',(0.,1.,0.));
#939=DIRECTION('',(-1.,0.,0.));
#940=AXIS2_PLACEMENT_3D('',#937,#938,#939);
#941=PLANE('',#940);
#942=DIRECTION('',(1.,0.,0.));
#943=VECTOR('',#942,1.);
#944=CARTESIAN_POINT('',(18.8515625,-25.4,-12.7));
#945=LINE('',#944,#943);
#946=CARTESIAN_POINT('',(18.8515625,-25.4,-12.7));
#947=VERTEX_POINT('',#946);
#948=EDGE_CURVE('E365',#915,#947,#945,.T.);
#949=ORIENTED_EDGE('',*,*,#948,.T.);
#950=DIRECTION('',(0.,0.,-1.));
#951=VECTOR('',#950,1.);
#952=CARTESIAN_POINT('',(18.8515625,-25.4,12.7));
#953=LINE('',#952,#951);
#954=CARTESIAN_POINT('',(18.8515625,-25.4,12.7));
#955=VERTEX_POINT('',#954);
#956=EDGE_CURVE('E384',#955,#947,#953,.T.);
#957=ORIENTED_EDGE('',*,*,#956,.F.);
#958=DIRECTION('',(1.,0.,0.));
#959=VECTOR('',#958,1.);
#960=CARTESIAN_POINT('',(18.8515625,-25.4,12.7));
#961=LINE('',#960,#959);
#962=EDGE_CURVE('E544',#923,#955,#961,.T.);
#963=ORIENTED_EDGE('',*,*,#962,.F.);
#964=ORIENTED_EDGE('',*,*,#924,.T.);
#965=EDGE_LOOP('',(#949,#957,#963,#964));
#966=FACE_BOUND('',#965,.T.);
#967=ADVANCED_FACE('F676',(#966),#941,.F.);
#968=CARTESIAN_POINT('',(18.8515625,-23.6140625,12.7));
#969=DIRECTION('',(0.,0.,-1.));
#970=DIRECTION('',(-1.,0.,0.));
#971=AXIS2_PLACEMENT_3D('',#968,#969,#970);
#972=CYLINDRICAL_SURFACE('',#971,1.7859375);
#973=CARTESIAN_POINT('',(18.8515625,-23.6140625,-12.7));
#974=DIRECTION('',(0.,0.,1.));
#975=DIRECTION('',(1.,0.,0.));
#976=AXIS2_PLACEMENT_3D('',#973,#974,#975);
#977=CIRCLE('',#976,1.7859375);
#978=CARTESIAN_POINT('',(20.6375,-23.6140625,-12.7));
#979=VERTEX_POINT('',#978);
#980=EDGE_CURVE('E364',#947,#979,#977,.T.);
#981=ORIENTED_EDGE('',*,*,#980,.T.);
#982=DIRECTION('',(0.,0.,-1.));
#983=VECTOR('',#982,1.);
#984=CARTESIAN_POINT('',(20.6375,-23.6140625,12.7));
#985=LINE('',#984,#983);
#986=CARTESIAN_POINT('',(20.6375,-23.6140625,12.7));
#987=VERTEX_POINT('',#986);
#988=EDGE_CURVE('E379',#987,#979,#985,.T.);
#989=ORIENTED_EDGE('',*,*,#988,.F.);
#990=CARTESIAN_POINT('',(18.8515625,-23.6140625,12.7));
#991=DIRECTION('',(0.,0.,1.));
#992=DIRECTION('',(1.,0.,0.));
#993=AXIS2_PLACEMENT_3D('',#990,#991,#992);
#994=CIRCLE('',#993,1.7859375);
#995=EDGE_CURVE('E545',#955,#987,#994,.T.);
#996=ORIENTED_EDGE('',*,*,#995,.F.);
#997=ORIENTED_EDGE('',*,*,#956,.T.);
#998=EDGE_LOOP('',(#981,#989,#996,#997));
#999=FACE_BOUND('',#998,.T.);
#1000=ADVANCED_FACE('F681',(#999),#972,.T.);
#1001=CARTESIAN_POINT('',(20.6375,-23.6140625,12.7));
#1002=DIRECTION('',(-1.,0.,0.));
#1003=DIRECTION('',(0.,-1.,0.));
#1004=AXIS2_PLACEMENT_3D('',#1001,#1002,#1003);
#1005=PLANE('',#1004);
#1006=DIRECTION('',(0.,1.,0.));
#1007=VECTOR('',#1006,1.);
#1008=CARTESIAN_POINT('',(20.6375,-23.6140625,-12.7));
#1009=LINE('',#1008,#1007);
#1010=CARTESIAN_POINT('',(20.6375,23.6140625,-12.7));
#1011=VERTEX_POINT('',#1010);
#1012=EDGE_CURVE('E366',#979,#1011,#1009,.T.);
#1013=ORIENTED_EDGE('',*,*,#1012,.T.);
#1014=DIRECTION('',(0.,0.,-1.));
#1015=VECTOR('',#1014,1.);
#1016=CARTESIAN_POINT('',(20.6375,23.6140625,12.7));
#1017=LINE('',#1016,#1015);
#1018=CARTESIAN_POINT('',(20.6375,23.6140625,12.7));
#1019=VERTEX_POINT('',#1018);
#1020=EDGE_CURVE('E380',#1019,#1011,#1017,.T.);
#1021=ORIENTED_EDGE('',*,*,#1020,.F.);
#1022=DIRECTION('',(0.,1.,0.));
#1023=VECTOR('',#1022,1.);
#1024=CARTESIAN_POINT('',(20.6375,-23.6140625,12.7));
#1025=LINE('',#1024,#1023);
#1026=EDGE_CURVE('E547',#987,#1019,#1025,.T.);
#1027=ORIENTED_EDGE('',*,*,#1026,.F.);
#1028=ORIENTED_EDGE('',*,*,#988,.T.);
#1029=EDGE_LOOP('',(#1013,#1021,#1027,#1028));
#1030=FACE_BOUND('',#1029,.T.);
#1031=ADVANCED_FACE('F552',(#1030),#1005,.F.);
#1032=CARTESIAN_POINT('',(18.8515625,23.6140625,12.7));
#1033=DIRECTION('',(0.,0.,-1.));
#1034=DIRECTION('',(-1.,0.,0.));
#1035=AXIS2_PLACEMENT_3D('',#1032,#1033,#1034);
#1036=CYLINDRICAL_SURFACE('',#1035,1.7859375);
#1037=CARTESIAN_POINT('',(18.8515625,23.6140625,-12.7));
#1038=DIRECTION('',(0.,0.,1.));
#1039=DIRECTION('',(-1.,0.,0.));
#1040=AXIS2_PLACEMENT_3D('',#1037,#1038,#1039);
#1041=CIRCLE('',#1040,1.7859375);
#1042=CARTESIAN_POINT('',(18.8515625,25.4,-12.7));
#1043=VERTEX_POINT('',#1042);
#1044=EDGE_CURVE('E368',#1011,#1043,#1041,.T.);
#1045=ORIENTED_EDGE('',*,*,#1044,.T.);
#1046=DIRECTION('',(0.,0.,-1.));
#1047=VECTOR('',#1046,1.);
#1048=CARTESIAN_POINT('',(18.8515625,25.4,12.7));
#1049=LINE('',#1048,#1047);
#1050=CARTESIAN_POINT('',(18.8515625,25.4,12.7));
#1051=VERTEX_POINT('',#1050);
#1052=EDGE_CURVE('E295',#1051,#1043,#1049,.T.);
#1053=ORIENTED_EDGE('',*,*,#1052,.F.);
#1054=CARTESIAN_POINT('',(18.8515625,23.6140625,12.7));
#1055=DIRECTION('',(0.,0.,1.));
#1056=DIRECTION('',(-1.,0.,0.));
#1057=AXIS2_PLACEMENT_3D('',#1054,#1055,#1056);
#1058=CIRCLE('',#1057,1.7859375);
#1059=EDGE_CURVE('E281',#1019,#1051,#1058,.T.);
#1060=ORIENTED_EDGE('',*,*,#1059,.F.);
#1061=ORIENTED_EDGE('',*,*,#1020,.T.);
#1062=EDGE_LOOP('',(#1045,#1053,#1060,#1061));
#1063=FACE_BOUND('',#1062,.T.);
#1064=ADVANCED_FACE('F558',(#1063),#1036,.T.);
#1065=CARTESIAN_POINT('',(18.8515625,25.4,12.7));
#1066=DIRECTION('',(0.,-1.,0.));
#1067=DIRECTION('',(1.,0.,0.));
#1068=AXIS2_PLACEMENT_3D('',#1065,#1066,#1067);
#1069=PLANE('',#1068);
#1070=DIRECTION('',(-1.,0.,0.));
#1071=VECTOR('',#1070,1.);
#1072=CARTESIAN_POINT('',(18.8515625,25.4,-12.7));
#1073=LINE('',#1072,#1071);
#1074=CARTESIAN_POINT('',(11.3109375,25.4,-12.7));
#1075=VERTEX_POINT('',#1074);
#1076=EDGE_CURVE('E291',#1043,#1075,#1073,.T.);
#1077=ORIENTED_EDGE('',*,*,#1076,.T.);
#1078=DIRECTION('',(0.,0.,-1.));
#1079=VECTOR('',#1078,1.);
#1080=CARTESIAN_POINT('',(11.3109375,25.4,12.7));
#1081=LINE('',#1080,#1079);
#1082=CARTESIAN_POINT('',(11.3109375,25.4,12.7));
#1083=VERTEX_POINT('',#1082);
#1084=EDGE_CURVE('E288',#1083,#1075,#1081,.T.);
#1085=ORIENTED_EDGE('',*,*,#1084,.F.);
#1086=DIRECTION('',(-1.,0.,0.));
#1087=VECTOR('',#1086,1.);
#1088=CARTESIAN_POINT('',(18.8515625,25.4,12.7));
#1089=LINE('',#1088,#1087);
#1090=EDGE_CURVE('E276',#1051,#1083,#1089,.T.);
#1091=ORIENTED_EDGE('',*,*,#1090,.F.);
#1092=ORIENTED_EDGE('',*,*,#1052,.T.);
#1093=EDGE_LOOP('',(#1077,#1085,#1091,#1092));
#1094=FACE_BOUND('',#1093,.T.);
#1095=ADVANCED_FACE('F293',(#1094),#1069,.F.);
#1096=CARTESIAN_POINT('',(11.3109375,23.6140625,12.7));
#1097=DIRECTION('',(0.,0.,-1.));
#1098=DIRECTION('',(-1.,0.,0.));
#1099=AXIS2_PLACEMENT_3D('',#1096,#1097,#1098);
#1100=CYLINDRICAL_SURFACE('',#1099,1.7859375);
#1101=CARTESIAN_POINT('',(11.3109375,23.6140625,-12.7));
#1102=DIRECTION('',(0.,0.,1.));
#1103=DIRECTION('',(-1.,0.,0.));
#1104=AXIS2_PLACEMENT_3D('',#1101,#1102,#1103);
#1105=CIRCLE('',#1104,1.7859375);
#1106=CARTESIAN_POINT('',(9.525,23.6140625,-12.7));
#1107=VERTEX_POINT('',#1106);
#1108=EDGE_CURVE('E166',#1075,#1107,#1105,.T.);
#1109=ORIENTED_EDGE('',*,*,#1108,.T.);
#1110=DIRECTION('',(0.,0.,-1.));
#1111=VECTOR('',#1110,1.);
#1112=CARTESIAN_POINT('',(9.525,23.6140625,12.7));
#1113=LINE('',#1112,#1111);
#1114=CARTESIAN_POINT('',(9.525,23.6140625,12.7));
#1115=VERTEX_POINT('',#1114);
#1116=EDGE_CURVE('E294',#1115,#1107,#1113,.T.);
#1117=ORIENTED_EDGE('',*,*,#1116,.F.);
#1118=CARTESIAN_POINT('',(11.3109375,23.6140625,12.7));
#1119=DIRECTION('',(0.,0.,1.));
#1120=DIRECTION('',(-1.,0.,0.));
#1121=AXIS2_PLACEMENT_3D('',#1118,#1119,#1120);
#1122=CIRCLE('',#1121,1.7859375);
#1123=EDGE_CURVE('E282',#1083,#1115,#1122,.T.);
#1124=ORIENTED_EDGE('',*,*,#1123,.F.);
#1125=ORIENTED_EDGE('',*,*,#1084,.T.);
#1126=EDGE_LOOP('',(#1109,#1117,#1124,#1125));
#1127=FACE_BOUND('',#1126,.T.);
#1128=ADVANCED_FACE('F300',(#1127),#1100,.T.);
#1129=CARTESIAN_POINT('',(9.525,23.6140625,12.7));
#1130=DIRECTION('',(1.,0.,0.));
#1131=DIRECTION('',(0.,1.,0.));
#1132=AXIS2_PLACEMENT_3D('',#1129,#1130,#1131);
#1133=PLANE('',#1132);
#1134=DIRECTION('',(0.,-1.,0.));
#1135=VECTOR('',#1134,1.);
#1136=CARTESIAN_POINT('',(9.525,23.6140625,-12.7));
#1137=LINE('',#1136,#1135);
#1138=EDGE_CURVE('E172',#1107,#29,#1137,.T.);
#1139=ORIENTED_EDGE('',*,*,#1138,.T.);
#1140=ORIENTED_EDGE('',*,*,#54,.F.);
#1141=DIRECTION('',(0.,-1.,0.));
#1142=VECTOR('',#1141,1.);
#1143=CARTESIAN_POINT('',(9.525,23.6140625,12.7));
#1144=LINE('',#1143,#1142);
#1145=EDGE_CURVE('E54',#1115,#47,#1144,.T.);
#1146=ORIENTED_EDGE('',*,*,#1145,.F.);
#1147=ORIENTED_EDGE('',*,*,#1116,.T.);
#1148=EDGE_LOOP('',(#1139,#1140,#1146,#1147));
#1149=FACE_BOUND('',#1148,.T.);
#1150=ADVANCED_FACE('F557',(#1149),#1133,.F.);
#1151=CARTESIAN_POINT('',(-11.3109375,23.6140625,12.7));
#1152=DIRECTION('',(0.,0.,-1.));
#1153=DIRECTION('',(-1.,0.,0.));
#1154=AXIS2_PLACEMENT_3D('',#1151,#1152,#1153);
#1155=PLANE('',#1154);
#1156=ORIENTED_EDGE('',*,*,#48,.T.);
#1157=ORIENTED_EDGE('',*,*,#84,.T.);
#1158=ORIENTED_EDGE('',*,*,#115,.T.);
#1159=ORIENTED_EDGE('',*,*,#146,.T.);
#1160=ORIENTED_EDGE('',*,*,#177,.T.);
#1161=ORIENTED_EDGE('',*,*,#208,.T.);
#1162=ORIENTED_EDGE('',*,*,#239,.T.);
#1163=ORIENTED_EDGE('',*,*,#270,.T.);
#1164=ORIENTED_EDGE('',*,*,#301,.T.);
#1165=ORIENTED_EDGE('',*,*,#332,.T.);
#1166=ORIENTED_EDGE('',*,*,#365,.T.);
#1167=ORIENTED_EDGE('',*,*,#396,.T.);
#1168=ORIENTED_EDGE('',*,*,#429,.T.);
#1169=ORIENTED_EDGE('',*,*,#460,.T.);
#1170=ORIENTED_EDGE('',*,*,#493,.T.);
#1171=ORIENTED_EDGE('',*,*,#524,.T.);
#1172=ORIENTED_EDGE('',*,*,#557,.T.);
#1173=ORIENTED_EDGE('',*,*,#588,.T.);
#1174=ORIENTED_EDGE('',*,*,#619,.T.);
#1175=ORIENTED_EDGE('',*,*,#650,.T.);
#1176=ORIENTED_EDGE('',*,*,#681,.T.);
#1177=ORIENTED_EDGE('',*,*,#712,.T.);
#1178=ORIENTED_EDGE('',*,*,#743,.T.);
#1179=ORIENTED_EDGE('',*,*,#774,.T.);
#1180=ORIENTED_EDGE('',*,*,#805,.T.);
#1181=ORIENTED_EDGE('',*,*,#836,.T.);
#1182=ORIENTED_EDGE('',*,*,#867,.T.);
#1183=ORIENTED_EDGE('',*,*,#898,.T.);
#1184=ORIENTED_EDGE('',*,*,#931,.T.);
#1185=ORIENTED_EDGE('',*,*,#962,.T.);
#1186=ORIENTED_EDGE('',*,*,#995,.T.);
#1187=ORIENTED_EDGE('',*,*,#1026,.T.);
#1188=ORIENTED_EDGE('',*,*,#1059,.T.);
#1189=ORIENTED_EDGE('',*,*,#1090,.T.);
#1190=ORIENTED_EDGE('',*,*,#1123,.T.);
#1191=ORIENTED_EDGE('',*,*,#1145,.T.);
#1192=EDGE_LOOP('',(#1156,#1157,#1158,#1159,#1160,#1161,#1162,#1163,#1164,#1165,#1166,#1167,
#1168,#1169,#1170,#1171,#1172,#1173,#1174,#1175,#1176,#1177,#1178,#1179,#1180,#1181,#1182,#1183,
#1184,#1185,#1186,#1187,#1188,#1189,#1190,#1191));
#1193=FACE_BOUND('',#1192,.T.);
#1194=ADVANCED_FACE('F283',(#1193),#1155,.F.);
#1195=CARTESIAN_POINT('',(-11.3109375,23.6140625,-12.7));
#1196=DIRECTION('',(0.,0.,-1.));
#1197=DIRECTION('',(-1.,0.,0.));
#1198=AXIS2_PLACEMENT_3D('',#1195,#1196,#1197);
#1199=PLANE('',#1198);
#1200=ORIENTED_EDGE('',*,*,#32,.F.);
#1201=ORIENTED_EDGE('',*,*,#1138,.F.);
#1202=ORIENTED_EDGE('',*,*,#1108,.F.);
#1203=ORIENTED_EDGE('',*,*,#1076,.F.);
#1204=ORIENTED_EDGE('',*,*,#1044,.F.);
#1205=ORIENTED_EDGE('',*,*,#1012,.F.);
#1206=ORIENTED_EDGE('',*,*,#980,.F.);
#1207=ORIENTED_EDGE('',*,*,#948,.F.);
#1208=ORIENTED_EDGE('',*,*,#916,.F.);
#1209=ORIENTED_EDGE('',*,*,#884,.F.);
#1210=ORIENTED_EDGE('',*,*,#853,.F.);
#1211=ORIENTED_EDGE('',*,*,#822,.F.);
#1212=ORIENTED_EDGE('',*,*,#791,.F.);
#1213=ORIENTED_EDGE('',*,*,#760,.F.);
#1214=ORIENTED_EDGE('',*,*,#729,.F.);
#1215=ORIENTED_EDGE('',*,*,#698,.F.);
#1216=ORIENTED_EDGE('',*,*,#667,.F.);
#1217=ORIENTED_EDGE('',*,*,#636,.F.);
#1218=ORIENTED_EDGE('',*,*,#605,.F.);
#1219=ORIENTED_EDGE('',*,*,#574,.F.);
#1220=ORIENTED_EDGE('',*,*,#542,.F.);
#1221=ORIENTED_EDGE('',*,*,#510,.F.);
#1222=ORIENTED_EDGE('',*,*,#478,.F.);
#1223=ORIENTED_EDGE('',*,*,#446,.F.);
#1224=ORIENTED_EDGE('',*,*,#414,.F.);
#1225=ORIENTED_EDGE('',*,*,#382,.F.);
#1226=ORIENTED_EDGE('',*,*,#350,.F.);
#1227=ORIENTED_EDGE('',*,*,#318,.F.);
#1228=ORIENTED_EDGE('',*,*,#287,.F.);
#1229=ORIENTED_EDGE('',*,*,#256,.F.);
#1230=ORIENTED_EDGE('',*,*,#225,.F.);
#1231=ORIENTED_EDGE('',*,*,#194,.F.);
#1232=ORIENTED_EDGE('',*,*,#163,.F.);
#1233=ORIENTED_EDGE('',*,*,#132,.F.);
#1234=ORIENTED_EDGE('',*,*,#101,.F.);
#1235=ORIENTED_EDGE('',*,*,#70,.F.);
#1236=EDGE_LOOP('',(#1200,#1201,#1202,#1203,#1204,#1205,#1206,#1207,#1208,#1209,#1210,#1211,
#1212,#1213,#1214,#1215,#1216,#1217,#1218,#1219,#1220,#1221,#1222,#1223,#1224,#1225,#1226,#1227,
#1228,#1229,#1230,#1231,#1232,#1233,#1234,#1235));
#1237=FACE_BOUND('',#1236,.T.);
#1238=ADVANCED_FACE('F478',(#1237),#1199,.T.);
#1239=CLOSED_SHELL('',(#58,#89,#120,#151,#182,#213,#244,#275,#306,#337,#370,#401,#434,#465,#498,
#529,#562,#593,#624,#655,#686,#717,#748,#779,#810,#841,#872,#903,#936,#967,#1000,#1031,#1064,
#1095,#1128,#1150,#1194,#1238));
#1240=MANIFOLD_SOLID_BREP('B2',#1239);
#1241=ADVANCED_BREP_SHAPE_REPRESENTATION('',(#18,#1240),#14);
#1242=SHAPE_DEFINITION_REPRESENTATION(#9,#1241);
ENDSEC;
END-ISO-10303-21;
